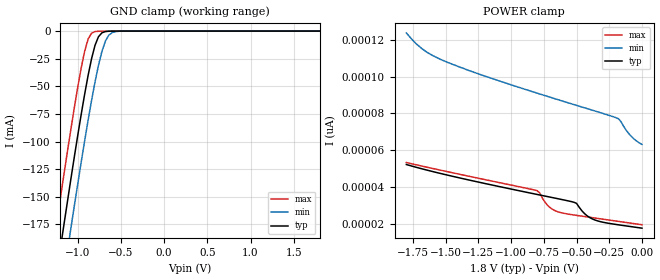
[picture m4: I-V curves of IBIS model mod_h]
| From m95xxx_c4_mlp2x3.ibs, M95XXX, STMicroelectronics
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|   Model mod_h
[Model]   mod_h
Model_type Input
Vinl   =   0.540V
Vinh   =   1.260V
C_comp   2.119pF   2.023pF   2.323pF
[Temperature Range]   25.0000   0.1050k   -40.0000
[Voltage Range]   1.8000V   1.7000V   2.0000V
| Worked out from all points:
|   GND clamp passes 1 mA (typ) near -0.70 V on its own axis
[GND_clamp]
|Voltage   I(typ)   I(min)   I(max)
-1.8V     -520.9mA   -565.1mA   -476.4mA
-1.28V    -238.6mA   -283.5mA   -193mA
-1.24V    -217.4mA   -262.3mA   -171.8mA
-1.16V    -175.4mA   -220.3mA   -129.9mA
-1.08V    -134.3mA   -178.9mA   -89.23mA
-920mV    -57.23mA   -99.44mA   -18.3mA
-840mV    -25.05mA   -62.86mA   -1.898mA
-800mV    -12.93mA   -46.11mA   -437.7uA
-720mV    -1.573mA   -18.37mA   -100.4uA
-680mV    -437.7uA   -9.119mA   -81.04uA
-600mV    -50.37uA   -1.304mA   -55.9uA
1.8V      15.87pA    456.8pA    13.84pA
[POWER_clamp]
|Voltage   I(typ)   I(min)   I(max)
-1.8V     52.4pA     123.6pA    53.47pA
-1.68V    50.06pA    115pA      51.53pA
-1.48V    46.57pA    107.5pA    48.43pA
-800mV    36.19pA    90.98pA    38.21pA
-740mV    35.32pA    89.65pA    31.92pA
-680mV    34.45pA    88.33pA    28.02pA
-520mV    31.98pA    84.83pA    25.1pA
-440mV    25.93pA    83.09pA    24.27pA
-380mV    22.99pA    81.8pA     23.66pA
-180mV    19.78pA    77.17pA    21.63pA
-80mV     18.77pA    67.5pA     20.62pA
0V        17.97pA    63.24pA    19.82pA
